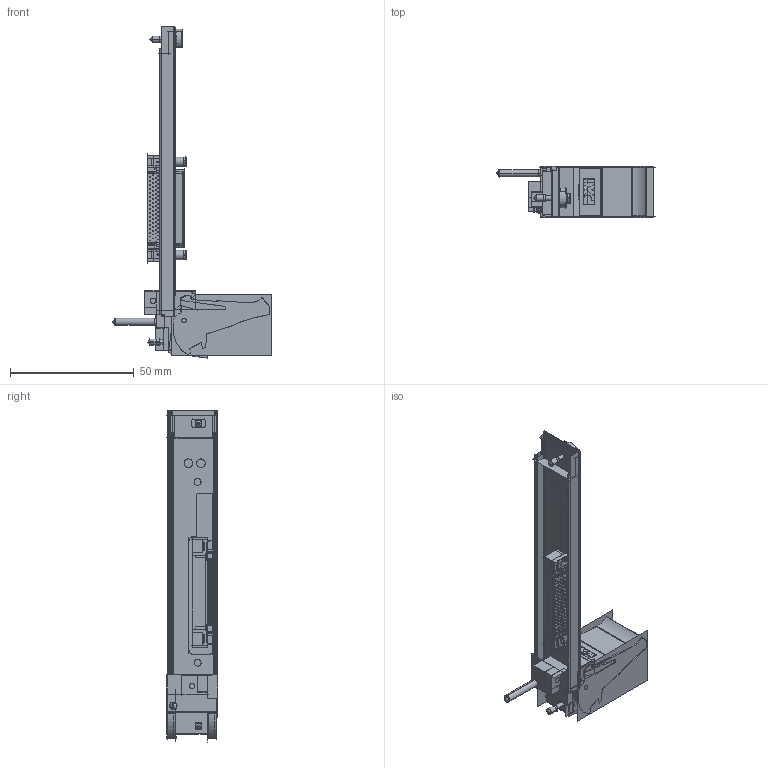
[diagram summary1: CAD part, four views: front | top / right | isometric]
IGES file: header records copied from the file, then geometry measured from it (millimetres).
Start section:  PTC IGES file: cu_pxie-6571.igs
Global section: file name: cu_pxie-6571.igs; native system: Creo Parametric by PTC Inc.; preprocessor: 2017480; author: huydo; organization: Unknown; date: 20180629.085439; units: inch
Bounding box: 64.34 x 20.97 x 134.23 mm (x, y, z)
Surface area: 53125.6 mm2 (no closed solid volume)
Topology: 0 solids, 0 shells, 4224 faces, 60594 edges, 78566 vertices
Faces by surface type: bspline 3314, revolution 894, extrusion 16
